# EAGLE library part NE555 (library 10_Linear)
TIMER

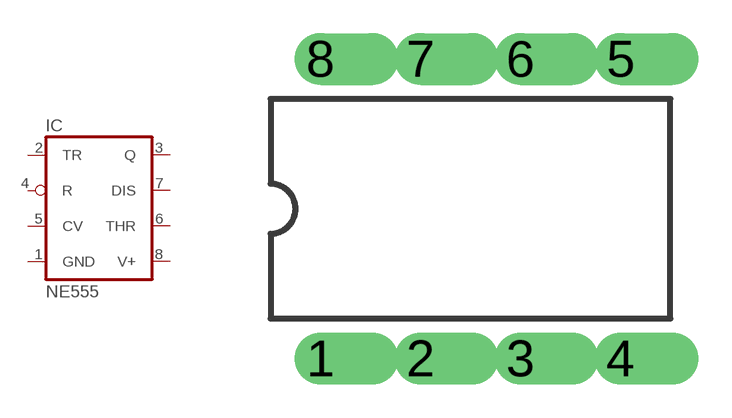
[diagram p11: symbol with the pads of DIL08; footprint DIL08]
Designator prefix IC

## NE555N  [DIL08]
1  GND  pwr
2  TR  in
3  Q  out
4  R  in
5  CV  in
6  THR  in
7  DIS  in
8  V+  pwr

## Footprint DIL08 (pad centres in mm)
Dual In Line 8
drill 0.813 offset: 1 -3.81,-3.81; 2 -1.27,-3.81; 3 1.27,-3.81; 4 3.81,-3.81; 5 3.81,3.81; 6 1.27,3.81; 7 -1.27,3.81; 8 -3.81,3.81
